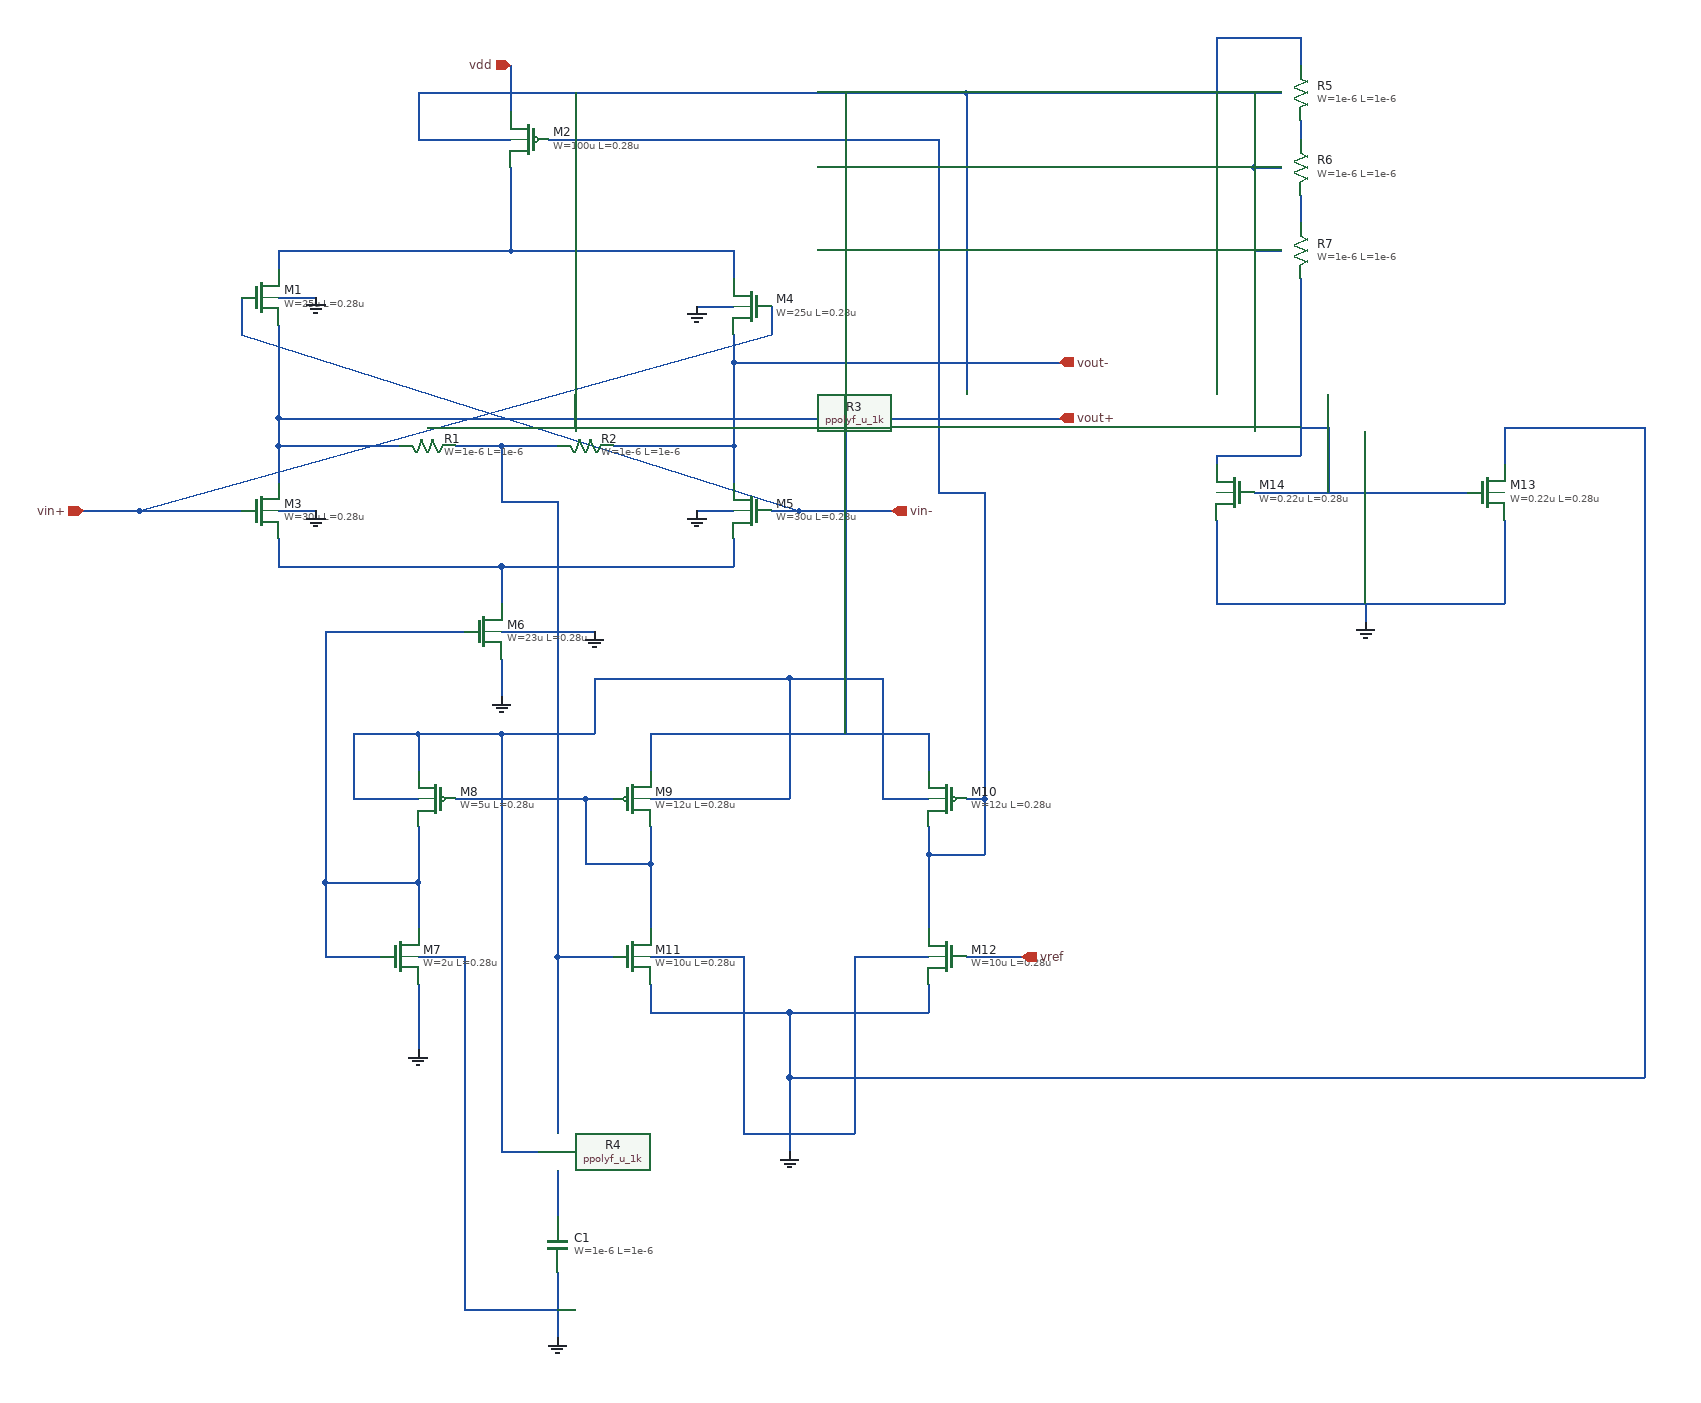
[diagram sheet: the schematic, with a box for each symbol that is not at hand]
v {xschem version=3.4.8RC file_version=1.3}
G {}
K {}
V {}
S {}
F {}
E {}
P 4 1 580 -340 {}
P 4 1 1490 -830 {}
N 300 -1070 300 -1030 {lab=vout+}
N 790 -1070 790 -1030 {lab=vout-}
N 300 -1280 300 -1260 {lab=#net1}
N 550 -1280 790 -1280 {lab=#net1}
N 790 -1280 790 -1250 {lab=#net1}
N 300 -970 300 -940 {lab=#net2}
N 540 -940 790 -940 {lab=#net2}
N 790 -970 790 -940 {lab=#net2}
N 300 -1070 430 -1070 {lab=vout+}
N 540 -1070 600 -1070 {lab=#net3}
N 490 -1070 540 -1070 {lab=#net3}
N 660 -1070 790 -1070 {lab=vout-}
N 790 -1160 1140 -1160 {lab=vout-}
N 300 -1100 1140 -1100 {lab=vout+}
N 550 -1370 550 -1280 {lab=#net1}
N 550 -1480 550 -1430 {lab=vdd}
N 540 -940 540 -900 {lab=#net2}
N 540 -840 540 -800 {lab=0}
N 350 -870 500 -870 {lab=#net4}
N 350 -600 350 -520 {lab=#net4}
N 450 -600 450 -550 {lab=#net4}
N 630 -690 660 -690 {lab=#net5}
N 700 -760 700 -720 {lab=vdd}
N 840 -760 1000 -760 {lab=vdd}
N 1000 -760 1000 -720 {lab=vdd}
N 700 -620 700 -550 {lab=#net5}
N 1000 -630 1000 -550 {lab=#net6}
N 700 -490 700 -460 {lab=0}
N 850 -460 1000 -460 {lab=0}
N 1000 -490 1000 -460 {lab=0}
N 600 -520 600 -450 {lab=#net3}
N 600 -520 660 -520 {lab=#net3}
N 600 -1010 600 -520 {lab=#net3}
N 540 -1010 600 -1010 {lab=#net3}
N 540 -1070 540 -1010 {lab=#net3}
N 450 -490 450 -420 {lab=0}
N 1040 -520 1100 -520 {lab=vref}
N 850 -360 850 -310 {lab=0}
N 350 -520 410 -520 {lab=#net4}
N 850 -460 850 -420 {lab=0}
N 1040 -690 1060 -690 {lab=#net6}
N 1000 -630 1060 -630 {lab=#net6}
N 1060 -690 1060 -630 {lab=#net6}
N 590 -1400 1010 -1400 {lab=#net6}
N 1060 -1020 1060 -690 {lab=#net6}
N 1010 -1020 1060 -1020 {lab=#net6}
N 1010 -1400 1010 -1020 {lab=#net6}
N 830 -1220 830 -1190 {lab=vin+}
N 150 -1000 830 -1190 {lab=vin+}
N 150 -1000 260 -1000 {lab=vin+}
N 90 -1000 150 -1000 {lab=vin+}
N 260 -1230 260 -1190 {lab=vin-}
N 260 -1190 860 -1000 {lab=vin-}
N 830 -1000 860 -1000 {lab=vin-}
N 860 -1000 960 -1000 {lab=vin-}
N 300 -1000 340 -1000 {lab=0}
N 300 -1230 340 -1230 {lab=0}
N 750 -1220 790 -1220 {lab=0}
N 750 -1000 790 -1000 {lab=0}
N 540 -870 580 -870 {lab=0}
N 450 -760 450 -720 {lab=vdd}
N 630 -690 630 -620 {lab=#net5}
N 630 -620 700 -620 {lab=#net5}
N 350 -600 450 -600 {lab=#net4}
N 300 -1100 300 -1070 {lab=vout+}
N 790 -1160 790 -1070 {lab=vout-}
N 790 -1190 790 -1160 {lab=vout-}
N 300 -1200 300 -1100 {lab=vout+}
N 300 -1280 550 -1280 {lab=#net1}
N 300 -940 540 -940 {lab=#net2}
N 700 -760 840 -760 {lab=vdd}
N 700 -460 850 -460 {lab=0}
N 1000 -660 1000 -630 {lab=#net6}
N 490 -690 630 -690 {lab=#net5}
N 700 -660 700 -620 {lab=#net5}
N 350 -870 350 -600 {lab=#net4}
N 450 -660 450 -600 {lab=#net4}
N 600 -450 600 -390 {lab=#net3}
N 600 -290 600 -240 {lab=#net7}
N 600 -180 600 -110 {lab=0}
N 550 -1450 1030 -1450 {lab=vdd}
N 1030 -1450 1040 -1450 {lab=vdd}
N 1040 -1450 1040 -1130 {lab=vdd}
N 450 -1450 550 -1450 {lab=vdd}
N 450 -1450 450 -1400 {lab=vdd}
N 450 -1400 550 -1400 {lab=vdd}
N 450 -520 500 -520 {lab=0}
N 500 -520 500 -140 {lab=0}
N 500 -140 600 -140 {lab=0}
N 910 -1450 910 -760 {lab=vdd}
N 700 -690 850 -690 {lab=vdd}
N 850 -820 850 -690 {lab=vdd}
N 850 -820 910 -820 {lab=vdd}
N 950 -690 1000 -690 {lab=vdd}
N 950 -820 950 -690 {lab=vdd}
N 910 -820 950 -820 {lab=vdd}
N 540 -760 540 -360 {lab=vdd}
N 540 -760 640 -760 {lab=vdd}
N 640 -820 640 -760 {lab=vdd}
N 640 -820 850 -820 {lab=vdd}
N 700 -520 800 -520 {lab=0}
N 800 -520 800 -330 {lab=0}
N 800 -330 850 -330 {lab=0}
N 850 -330 920 -330 {lab=0}
N 920 -520 920 -330 {lab=0}
N 920 -520 1000 -520 {lab=0}
N 450 -760 540 -760 {lab=vdd}
N 580 -870 640 -870 {lab=0}
N 380 -690 450 -690 {lab=vdd}
N 380 -760 380 -690 {lab=vdd}
N 380 -760 450 -760 {lab=vdd}
N 1040 -1450 1380 -1450 {lab=vdd}
N 1310 -1510 1310 -1450 {lab=vdd}
N 1310 -1510 1400 -1510 {lab=vdd}
N 1400 -1510 1400 -1480 {lab=vdd}
N 1350 -1020 1580 -1020 {lab=#net8}
N 1310 -1060 1390 -1060 {lab=#net8}
N 1310 -1060 1310 -1050 {lab=#net8}
N 1430 -1090 1430 -1020 {lab=#net8}
N 1310 -990 1310 -900 {lab=0}
N 1310 -900 1620 -900 {lab=0}
N 1620 -990 1620 -900 {lab=0}
N 1470 -900 1470 -880 {lab=0}
N 1620 -1090 1620 -1060 {lab=0}
N 1620 -1090 1760 -1090 {lab=0}
N 960 -390 1770 -390 {lab=0}
N 850 -390 960 -390 {lab=0}
N 850 -390 850 -360 {lab=0}
N 850 -420 850 -400 {lab=0}
N 850 -400 850 -390 {lab=0}
N 1620 -1060 1620 -1050 {lab=0}
N 1400 -1420 1400 -1400 {lab=#net9}
N 1400 -1340 1400 -1310 {lab=#net10}
N 1400 -1250 1400 -1110 {lab=#net8}
N 1350 -1370 1380 -1370 {lab=vdd}
N 1350 -1450 1350 -1370 {lab=vdd}
N 1360 -1280 1380 -1280 {lab=vdd}
N 1350 -1370 1350 -1280 {lab=vdd}
N 1350 -1280 1360 -1280 {lab=vdd}
N 1390 -1060 1400 -1060 {lab=#net8}
N 1400 -1110 1400 -1060 {lab=#net8}
N 1400 -1090 1430 -1090 {lab=#net8}
N 1760 -1090 1770 -1090 {lab=0}
N 1770 -1090 1770 -390 {lab=0}
N 600 -390 600 -330 {lab=#net3}
N 540 -360 540 -310 {lab=vdd}
N 540 -310 580 -310 {lab=vdd}
N 460 -1090 630 -1090 {lab=vdd}
N 620 -1450 620 -1090 {lab=vdd}
C {symbols/nfet_03v3.sym} 280 -1230 0 0 {name=M1
L=0.28u
W=25u
nf=1
m=2
ad="'int((nf+1)/2) * W/nf * 0.18u'"
pd="'2*int((nf+1)/2) * (W/nf + 0.18u)'"
as="'int((nf+2)/2) * W/nf * 0.18u'"
ps="'2*int((nf+2)/2) * (W/nf + 0.18u)'"
nrd="'0.18u / W'" nrs="'0.18u / W'"
sa=0 sb=0 sd=0
model=nfet_03v3
spiceprefix=X
}
C {symbols/pfet_03v3.sym} 570 -1400 0 1 {name=M2
L=0.28u
W=100u
nf=1
m=1
ad="'int((nf+1)/2) * W/nf * 0.18u'"
pd="'2*int((nf+1)/2) * (W/nf + 0.18u)'"
as="'int((nf+2)/2) * W/nf * 0.18u'"
ps="'2*int((nf+2)/2) * (W/nf + 0.18u)'"
nrd="'0.18u / W'" nrs="'0.18u / W'"
sa=0 sb=0 sd=0
model=pfet_03v3
spiceprefix=X
}
C {symbols/nfet_03v3.sym} 280 -1000 0 0 {name=M3
L=0.28u
W=30u
nf=1
m=2
ad="'int((nf+1)/2) * W/nf * 0.18u'"
pd="'2*int((nf+1)/2) * (W/nf + 0.18u)'"
as="'int((nf+2)/2) * W/nf * 0.18u'"
ps="'2*int((nf+2)/2) * (W/nf + 0.18u)'"
nrd="'0.18u / W'" nrs="'0.18u / W'"
sa=0 sb=0 sd=0
model=nfet_03v3
spiceprefix=X
}
C {symbols/nfet_03v3.sym} 810 -1220 0 1 {name=M4
L=0.28u
W=25u
nf=1
m=2
ad="'int((nf+1)/2) * W/nf * 0.18u'"
pd="'2*int((nf+1)/2) * (W/nf + 0.18u)'"
as="'int((nf+2)/2) * W/nf * 0.18u'"
ps="'2*int((nf+2)/2) * (W/nf + 0.18u)'"
nrd="'0.18u / W'" nrs="'0.18u / W'"
sa=0 sb=0 sd=0
model=nfet_03v3
spiceprefix=X
}
C {symbols/nfet_03v3.sym} 810 -1000 0 1 {name=M5
L=0.28u
W=30u
nf=1
m=2
ad="'int((nf+1)/2) * W/nf * 0.18u'"
pd="'2*int((nf+1)/2) * (W/nf + 0.18u)'"
as="'int((nf+2)/2) * W/nf * 0.18u'"
ps="'2*int((nf+2)/2) * (W/nf + 0.18u)'"
nrd="'0.18u / W'" nrs="'0.18u / W'"
sa=0 sb=0 sd=0
model=nfet_03v3
spiceprefix=X
}
C {symbols/nfet_03v3.sym} 520 -870 0 0 {name=M6
L=0.28u
W=23u
nf=1
m=2
ad="'int((nf+1)/2) * W/nf * 0.18u'"
pd="'2*int((nf+1)/2) * (W/nf + 0.18u)'"
as="'int((nf+2)/2) * W/nf * 0.18u'"
ps="'2*int((nf+2)/2) * (W/nf + 0.18u)'"
nrd="'0.18u / W'" nrs="'0.18u / W'"
sa=0 sb=0 sd=0
model=nfet_03v3
spiceprefix=X
}
C {symbols/nfet_03v3.sym} 430 -520 0 0 {name=M7
L=0.28u
W=2u
nf=1
m=1
ad="'int((nf+1)/2) * W/nf * 0.18u'"
pd="'2*int((nf+1)/2) * (W/nf + 0.18u)'"
as="'int((nf+2)/2) * W/nf * 0.18u'"
ps="'2*int((nf+2)/2) * (W/nf + 0.18u)'"
nrd="'0.18u / W'" nrs="'0.18u / W'"
sa=0 sb=0 sd=0
model=nfet_03v3
spiceprefix=X
}
C {symbols/pfet_03v3.sym} 470 -690 0 1 {name=M8
L=0.28u
W=5u
nf=1
m=1
ad="'int((nf+1)/2) * W/nf * 0.18u'"
pd="'2*int((nf+1)/2) * (W/nf + 0.18u)'"
as="'int((nf+2)/2) * W/nf * 0.18u'"
ps="'2*int((nf+2)/2) * (W/nf + 0.18u)'"
nrd="'0.18u / W'" nrs="'0.18u / W'"
sa=0 sb=0 sd=0
model=pfet_03v3
spiceprefix=X
}
C {symbols/pfet_03v3.sym} 680 -690 0 0 {name=M9
L=0.28u
W=12u
nf=1
m=1
ad="'int((nf+1)/2) * W/nf * 0.18u'"
pd="'2*int((nf+1)/2) * (W/nf + 0.18u)'"
as="'int((nf+2)/2) * W/nf * 0.18u'"
ps="'2*int((nf+2)/2) * (W/nf + 0.18u)'"
nrd="'0.18u / W'" nrs="'0.18u / W'"
sa=0 sb=0 sd=0
model=pfet_03v3
spiceprefix=X
}
C {symbols/pfet_03v3.sym} 1020 -690 0 1 {name=M10
L=0.28u
W=12u
nf=1
m=1
ad="'int((nf+1)/2) * W/nf * 0.18u'"
pd="'2*int((nf+1)/2) * (W/nf + 0.18u)'"
as="'int((nf+2)/2) * W/nf * 0.18u'"
ps="'2*int((nf+2)/2) * (W/nf + 0.18u)'"
nrd="'0.18u / W'" nrs="'0.18u / W'"
sa=0 sb=0 sd=0
model=pfet_03v3
spiceprefix=X
}
C {symbols/nfet_03v3.sym} 680 -520 0 0 {name=M11
L=0.28u
W=10u
nf=1
m=1
ad="'int((nf+1)/2) * W/nf * 0.18u'"
pd="'2*int((nf+1)/2) * (W/nf + 0.18u)'"
as="'int((nf+2)/2) * W/nf * 0.18u'"
ps="'2*int((nf+2)/2) * (W/nf + 0.18u)'"
nrd="'0.18u / W'" nrs="'0.18u / W'"
sa=0 sb=0 sd=0
model=nfet_03v3
spiceprefix=X
}
C {symbols/nfet_03v3.sym} 1020 -520 0 1 {name=M12
L=0.28u
W=10u
nf=1
m=1
ad="'int((nf+1)/2) * W/nf * 0.18u'"
pd="'2*int((nf+1)/2) * (W/nf + 0.18u)'"
as="'int((nf+2)/2) * W/nf * 0.18u'"
ps="'2*int((nf+2)/2) * (W/nf + 0.18u)'"
nrd="'0.18u / W'" nrs="'0.18u / W'"
sa=0 sb=0 sd=0
model=nfet_03v3
spiceprefix=X
}
C {ipin.sym} 90 -1000 0 0 {name=p14 lab=vin+}
C {ipin.sym} 960 -1000 0 1 {name=p15 lab=vin-}
C {opin.sym} 1140 -1160 0 0 {name=p20 lab=vout-}
C {opin.sym} 1140 -1100 0 0 {name=p21 lab=vout+}
C {symbols/cap_mim_2f0fF.sym} 600 -210 0 0 {name=C1
W=1e-6
L=1e-6
model=cap_mim_2f0fF
spiceprefix=X
m=50}
C {symbols/ppolyf_u_1k.sym} 460 -1070 1 0 {name=R1
W=1e-6
L=1e-6
model=ppolyf_u_1k
spiceprefix=X
m=1}
C {symbols/ppolyf_u_1k.sym} 630 -1070 1 0 {name=R2
W=1e-6
L=1e-6
model=ppolyf_u_1k
spiceprefix=X
m=1}
C {symbols/ppolyf_u_1k.sym} 1060 -1130 0 0 {name=R3
W=1e-6
L=1e-6
model=ppolyf_u_1k
spiceprefix=X
m=12}
C {ipin.sym} 1100 -520 0 1 {name=p9 lab=vref}
C {ipin.sym} 550 -1480 0 0 {name=p16 lab=vdd}
C {gnd.sym} 850 -310 0 0 {name=l1 lab=0}
C {gnd.sym} 450 -420 0 0 {name=l2 lab=0}
C {gnd.sym} 600 -110 0 0 {name=l3 lab=0}
C {gnd.sym} 540 -800 0 0 {name=l5 lab=0}
C {gnd.sym} 340 -1000 3 0 {name=l6 lab=0}
C {gnd.sym} 340 -1230 3 0 {name=l7 lab=0}
C {gnd.sym} 750 -1220 1 1 {name=l8 lab=0}
C {gnd.sym} 750 -1000 1 1 {name=l9 lab=0}
C {gnd.sym} 640 -870 3 0 {name=l10 lab=0}
C {symbols/nfet_03v3.sym} 1600 -1020 0 0 {name=M13
L=0.28u
W=0.22u
nf=1
m=1
ad="'int((nf+1)/2) * W/nf * 0.18u'"
pd="'2*int((nf+1)/2) * (W/nf + 0.18u)'"
as="'int((nf+2)/2) * W/nf * 0.18u'"
ps="'2*int((nf+2)/2) * (W/nf + 0.18u)'"
nrd="'0.18u / W'" nrs="'0.18u / W'"
sa=0 sb=0 sd=0
model=nfet_03v3
spiceprefix=X
}
C {symbols/nfet_03v3.sym} 1330 -1020 0 1 {name=M14
L=0.28u
W=0.22u
nf=1
m=1
ad="'int((nf+1)/2) * W/nf * 0.18u'"
pd="'2*int((nf+1)/2) * (W/nf + 0.18u)'"
as="'int((nf+2)/2) * W/nf * 0.18u'"
ps="'2*int((nf+2)/2) * (W/nf + 0.18u)'"
nrd="'0.18u / W'" nrs="'0.18u / W'"
sa=0 sb=0 sd=0
model=nfet_03v3
spiceprefix=X
}
C {gnd.sym} 1470 -880 0 1 {name=l4 lab=0}
C {symbols/ppolyf_u_3k.sym} 1400 -1450 0 0 {name=R5
W=1e-6
L=1e-6
model=ppolyf_u_3k
spiceprefix=X
m=1}
C {symbols/ppolyf_u_3k.sym} 1400 -1370 0 0 {name=R6
W=1e-6
L=1e-6
model=ppolyf_u_3k
spiceprefix=X
m=1}
C {symbols/ppolyf_u_1k.sym} 600 -310 0 0 {name=R4
W=1e-6
L=1e-6
model=ppolyf_u_1k
spiceprefix=X
m=1}
C {symbols/ppolyf_u_3k.sym} 1400 -1280 0 0 {name=R7
W=1e-6
L=1e-6
model=ppolyf_u_3k
spiceprefix=X
m=1}
